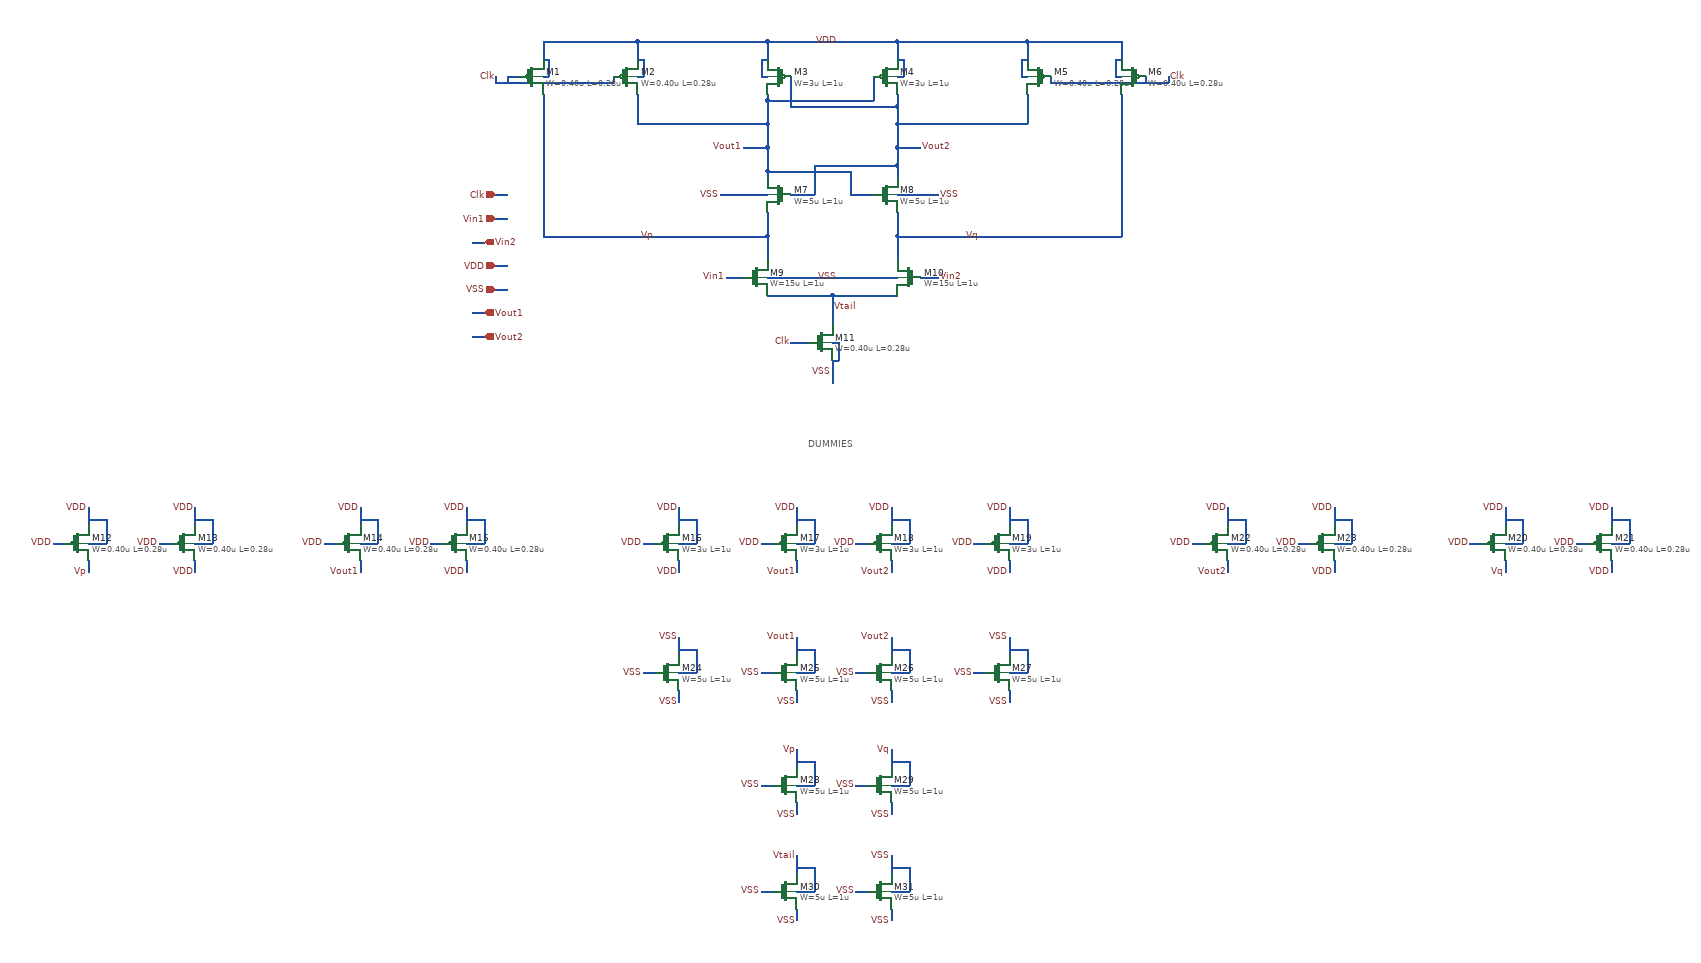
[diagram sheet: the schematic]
v {xschem version=3.4.8RC file_version=1.3}
G {}
K {}
V {}
S {}
F {}
E {}
P 4 1 2270 -1430 {}
T {DUMMIES} 2690 -860 0 0 0.4 0.4 {}
N 2730 -1100 2840 -1100 {lab=Vtail}
N 2730 -1100 2730 -1050 {lab=Vtail}
N 2840 -1200 2840 -1160 {lab=Vq}
N 2620 -1200 2620 -1160 {lab=Vp}
N 2730 -990 2730 -950 {lab=VSS}
N 2660 -1020 2690 -1020 {lab=Clk}
N 2550 -1130 2580 -1130 {lab=Vin1}
N 2880 -1130 2910 -1130 {lab=Vin2}
N 2240 -1440 2240 -1200 {lab=Vp}
N 2240 -1200 2620 -1200 {lab=Vp}
N 3220 -1440 3220 -1200 {lab=Vq}
N 2840 -1200 3220 -1200 {lab=Vq}
N 2620 -1310 2620 -1300 {lab=Vout1}
N 2840 -1320 2840 -1300 {lab=Vout2}
N 2660 -1270 2700 -1270 {lab=Vout2}
N 2700 -1320 2840 -1320 {lab=Vout2}
N 2760 -1270 2800 -1270 {lab=Vout1}
N 2760 -1310 2760 -1270 {lab=Vout1}
N 2620 -1310 2760 -1310 {lab=Vout1}
N 2700 -1320 2700 -1270 {lab=Vout2}
N 2400 -1440 2400 -1390 {lab=Vout1}
N 2400 -1390 2620 -1390 {lab=Vout1}
N 3060 -1440 3060 -1390 {lab=Vout2}
N 2840 -1390 3060 -1390 {lab=Vout2}
N 2800 -1470 2800 -1430 {lab=Vout1}
N 2620 -1430 2800 -1430 {lab=Vout1}
N 2660 -1470 2660 -1420 {lab=Vout2}
N 2660 -1420 2840 -1420 {lab=Vout2}
N 2580 -1350 2620 -1350 {lab=Vout1}
N 2840 -1350 2880 -1350 {lab=Vout2}
N 2160 -1460 2360 -1460 {lab=Clk}
N 3100 -1460 3300 -1460 {lab=Clk}
N 2240 -1530 2240 -1500 {lab=VDD}
N 3060 -1530 3220 -1530 {lab=VDD}
N 3220 -1530 3220 -1500 {lab=VDD}
N 3060 -1530 3060 -1500 {lab=VDD}
N 2840 -1530 2840 -1500 {lab=VDD}
N 2620 -1530 2620 -1500 {lab=VDD}
N 2400 -1530 2400 -1500 {lab=VDD}
N 2620 -1100 2730 -1100 {lab=Vtail}
N 2620 -1240 2620 -1200 {lab=Vp}
N 2840 -1240 2840 -1200 {lab=Vq}
N 2840 -1350 2840 -1320 {lab=Vout2}
N 2620 -1350 2620 -1310 {lab=Vout1}
N 2620 -1430 2620 -1390 {lab=Vout1}
N 2840 -1420 2840 -1390 {lab=Vout2}
N 2620 -1440 2620 -1430 {lab=Vout1}
N 2840 -1440 2840 -1420 {lab=Vout2}
N 2620 -1390 2620 -1350 {lab=Vout1}
N 2840 -1390 2840 -1350 {lab=Vout2}
N 2840 -1530 3060 -1530 {lab=VDD}
N 2620 -1530 2840 -1530 {lab=VDD}
N 2400 -1530 2620 -1530 {lab=VDD}
N 2240 -1530 2400 -1530 {lab=VDD}
N 2160 -1270 2180 -1270 {lab=Clk}
N 2160 -1230 2180 -1230 {lab=Vin1}
N 2120 -1190 2140 -1190 {lab=Vin2}
N 2160 -1150 2180 -1150 {lab=VDD}
N 2160 -1110 2180 -1110 {lab=VSS}
N 2120 -1070 2140 -1070 {lab=Vout1}
N 2120 -1030 2140 -1030 {lab=Vout2}
N 2360 -1470 2360 -1460 {lab=Clk}
N 2160 -1470 2160 -1460 {lab=Clk}
N 2240 -1470 2250 -1470 {lab=VDD}
N 2250 -1500 2250 -1470 {lab=VDD}
N 2240 -1500 2250 -1500 {lab=VDD}
N 2400 -1470 2410 -1470 {lab=VDD}
N 2410 -1500 2410 -1470 {lab=VDD}
N 2400 -1500 2410 -1500 {lab=VDD}
N 2610 -1470 2620 -1470 {lab=VDD}
N 2610 -1500 2610 -1470 {lab=VDD}
N 2610 -1500 2620 -1500 {lab=VDD}
N 2840 -1470 2850 -1470 {lab=VDD}
N 2850 -1500 2850 -1470 {lab=VDD}
N 2840 -1500 2850 -1500 {lab=VDD}
N 3050 -1470 3060 -1470 {lab=VDD}
N 3050 -1500 3050 -1470 {lab=VDD}
N 3050 -1500 3060 -1500 {lab=VDD}
N 3100 -1470 3100 -1460 {lab=Clk}
N 3260 -1470 3260 -1460 {lab=Clk}
N 3300 -1470 3300 -1460 {lab=Clk}
N 3210 -1470 3220 -1470 {lab=VDD}
N 3210 -1500 3210 -1470 {lab=VDD}
N 3210 -1500 3220 -1500 {lab=VDD}
N 2610 -1270 2620 -1270 {lab=VSS}
N 2840 -1270 2850 -1270 {lab=VSS}
N 2620 -1130 2630 -1130 {lab=VSS}
N 2830 -1130 2840 -1130 {lab=VSS}
N 2730 -1020 2740 -1020 {lab=VSS}
N 2740 -1020 2740 -990 {lab=VSS}
N 2730 -990 2740 -990 {lab=VSS}
N 2190 -1470 2200 -1470 {lab=Clk}
N 2180 -1470 2190 -1470 {lab=Clk}
N 2180 -1470 2180 -1460 {lab=Clk}
N 2740 -1130 2830 -1130 {lab=VSS}
N 2630 -1130 2740 -1130 {lab=VSS}
N 2850 -1270 2910 -1270 {lab=VSS}
N 2540 -1270 2610 -1270 {lab=VSS}
N 1410 -680 1430 -680 {lab=VDD}
N 1470 -740 1470 -710 {lab=VDD}
N 1470 -680 1500 -680 {lab=VDD}
N 1500 -720 1500 -680 {lab=VDD}
N 1470 -720 1500 -720 {lab=VDD}
N 1470 -650 1470 -630 {lab=Vp}
N 1590 -680 1610 -680 {lab=VDD}
N 1650 -740 1650 -710 {lab=VDD}
N 1650 -680 1680 -680 {lab=VDD}
N 1680 -720 1680 -680 {lab=VDD}
N 1650 -720 1680 -720 {lab=VDD}
N 1650 -650 1650 -630 {lab=VDD}
N 1870 -680 1890 -680 {lab=VDD}
N 1930 -740 1930 -710 {lab=VDD}
N 1930 -680 1960 -680 {lab=VDD}
N 1960 -720 1960 -680 {lab=VDD}
N 1930 -720 1960 -720 {lab=VDD}
N 1930 -650 1930 -630 {lab=Vout1}
N 2050 -680 2070 -680 {lab=VDD}
N 2110 -740 2110 -710 {lab=VDD}
N 2110 -680 2140 -680 {lab=VDD}
N 2140 -720 2140 -680 {lab=VDD}
N 2110 -720 2140 -720 {lab=VDD}
N 2110 -650 2110 -630 {lab=VDD}
N 2410 -680 2430 -680 {lab=VDD}
N 2470 -740 2470 -710 {lab=VDD}
N 2470 -680 2500 -680 {lab=VDD}
N 2500 -720 2500 -680 {lab=VDD}
N 2470 -720 2500 -720 {lab=VDD}
N 2470 -650 2470 -630 {lab=VDD}
N 2610 -680 2630 -680 {lab=VDD}
N 2670 -740 2670 -710 {lab=VDD}
N 2670 -680 2700 -680 {lab=VDD}
N 2700 -720 2700 -680 {lab=VDD}
N 2670 -720 2700 -720 {lab=VDD}
N 2670 -650 2670 -630 {lab=Vout1}
N 2770 -680 2790 -680 {lab=VDD}
N 2830 -740 2830 -710 {lab=VDD}
N 2830 -680 2860 -680 {lab=VDD}
N 2860 -720 2860 -680 {lab=VDD}
N 2830 -720 2860 -720 {lab=VDD}
N 2830 -650 2830 -630 {lab=Vout2}
N 2970 -680 2990 -680 {lab=VDD}
N 3030 -740 3030 -710 {lab=VDD}
N 3030 -680 3060 -680 {lab=VDD}
N 3060 -720 3060 -680 {lab=VDD}
N 3030 -720 3060 -720 {lab=VDD}
N 3030 -650 3030 -630 {lab=VDD}
N 3810 -680 3830 -680 {lab=VDD}
N 3870 -740 3870 -710 {lab=VDD}
N 3870 -680 3900 -680 {lab=VDD}
N 3900 -720 3900 -680 {lab=VDD}
N 3870 -720 3900 -720 {lab=VDD}
N 3870 -650 3870 -630 {lab=Vq}
N 3990 -680 4010 -680 {lab=VDD}
N 4050 -740 4050 -710 {lab=VDD}
N 4050 -680 4080 -680 {lab=VDD}
N 4080 -720 4080 -680 {lab=VDD}
N 4050 -720 4080 -720 {lab=VDD}
N 4050 -650 4050 -630 {lab=VDD}
N 3340 -680 3360 -680 {lab=VDD}
N 3400 -740 3400 -710 {lab=VDD}
N 3400 -680 3430 -680 {lab=VDD}
N 3430 -720 3430 -680 {lab=VDD}
N 3400 -720 3430 -720 {lab=VDD}
N 3400 -650 3400 -630 {lab=Vout2}
N 3520 -680 3540 -680 {lab=VDD}
N 3580 -740 3580 -710 {lab=VDD}
N 3580 -680 3610 -680 {lab=VDD}
N 3610 -720 3610 -680 {lab=VDD}
N 3580 -720 3610 -720 {lab=VDD}
N 3580 -650 3580 -630 {lab=VDD}
N 2410 -460 2430 -460 {lab=VSS}
N 2470 -520 2470 -490 {lab=VSS}
N 2470 -460 2500 -460 {lab=VSS}
N 2500 -500 2500 -460 {lab=VSS}
N 2470 -500 2500 -500 {lab=VSS}
N 2470 -430 2470 -410 {lab=VSS}
N 2610 -460 2630 -460 {lab=VSS}
N 2670 -520 2670 -490 {lab=Vout1}
N 2670 -460 2700 -460 {lab=Vout1}
N 2700 -500 2700 -460 {lab=Vout1}
N 2670 -500 2700 -500 {lab=Vout1}
N 2670 -430 2670 -410 {lab=VSS}
N 2770 -460 2790 -460 {lab=VSS}
N 2830 -520 2830 -490 {lab=Vout2}
N 2830 -460 2860 -460 {lab=Vout2}
N 2860 -500 2860 -460 {lab=Vout2}
N 2830 -500 2860 -500 {lab=Vout2}
N 2830 -430 2830 -410 {lab=VSS}
N 2970 -460 2990 -460 {lab=VSS}
N 3030 -520 3030 -490 {lab=VSS}
N 3030 -460 3060 -460 {lab=VSS}
N 3060 -500 3060 -460 {lab=VSS}
N 3030 -500 3060 -500 {lab=VSS}
N 3030 -430 3030 -410 {lab=VSS}
N 2610 -270 2630 -270 {lab=VSS}
N 2670 -330 2670 -300 {lab=Vp}
N 2670 -270 2700 -270 {lab=Vp}
N 2700 -310 2700 -270 {lab=Vp}
N 2670 -310 2700 -310 {lab=Vp}
N 2670 -240 2670 -220 {lab=VSS}
N 2770 -270 2790 -270 {lab=VSS}
N 2830 -330 2830 -300 {lab=Vq}
N 2830 -270 2860 -270 {lab=Vq}
N 2860 -310 2860 -270 {lab=Vq}
N 2830 -310 2860 -310 {lab=Vq}
N 2830 -240 2830 -220 {lab=VSS}
N 2610 -90 2630 -90 {lab=VSS}
N 2670 -150 2670 -120 {lab=Vtail}
N 2670 -90 2700 -90 {lab=Vtail}
N 2700 -130 2700 -90 {lab=Vtail}
N 2670 -130 2700 -130 {lab=Vtail}
N 2670 -60 2670 -40 {lab=VSS}
N 2770 -90 2790 -90 {lab=VSS}
N 2830 -150 2830 -120 {lab=#net1}
N 2830 -90 2860 -90 {lab=#net1}
N 2860 -130 2860 -90 {lab=#net1}
N 2830 -130 2860 -130 {lab=#net1}
N 2830 -60 2830 -40 {lab=VSS}
C {symbols/pfet_03v3.sym} 2220 -1470 0 0 {name=M1
L=0.28u
W=0.40u
nf=1
m=1
ad="'int((nf+1)/2) * W/nf * 0.18u'"
pd="'2*int((nf+1)/2) * (W/nf + 0.18u)'"
as="'int((nf+2)/2) * W/nf * 0.18u'"
ps="'2*int((nf+2)/2) * (W/nf + 0.18u)'"
nrd="'0.18u / W'" nrs="'0.18u / W'"
sa=0 sb=0 sd=0
model=pfet_03v3
spiceprefix=X
}
C {symbols/pfet_03v3.sym} 2380 -1470 0 0 {name=M2
L=0.28u
W=0.40u
nf=1
m=1
ad="'int((nf+1)/2) * W/nf * 0.18u'"
pd="'2*int((nf+1)/2) * (W/nf + 0.18u)'"
as="'int((nf+2)/2) * W/nf * 0.18u'"
ps="'2*int((nf+2)/2) * (W/nf + 0.18u)'"
nrd="'0.18u / W'" nrs="'0.18u / W'"
sa=0 sb=0 sd=0
model=pfet_03v3
spiceprefix=X
}
C {symbols/pfet_03v3.sym} 2640 -1470 0 1 {name=M3
L=1u
W=3u
nf=1
m=1
ad="'int((nf+1)/2) * W/nf * 0.18u'"
pd="'2*int((nf+1)/2) * (W/nf + 0.18u)'"
as="'int((nf+2)/2) * W/nf * 0.18u'"
ps="'2*int((nf+2)/2) * (W/nf + 0.18u)'"
nrd="'0.18u / W'" nrs="'0.18u / W'"
sa=0 sb=0 sd=0
model=pfet_03v3
spiceprefix=X
}
C {symbols/pfet_03v3.sym} 2820 -1470 0 0 {name=M4
L=1u
W=3u
nf=1
m=1
ad="'int((nf+1)/2) * W/nf * 0.18u'"
pd="'2*int((nf+1)/2) * (W/nf + 0.18u)'"
as="'int((nf+2)/2) * W/nf * 0.18u'"
ps="'2*int((nf+2)/2) * (W/nf + 0.18u)'"
nrd="'0.18u / W'" nrs="'0.18u / W'"
sa=0 sb=0 sd=0
model=pfet_03v3
spiceprefix=X
}
C {symbols/pfet_03v3.sym} 3080 -1470 0 1 {name=M5
L=0.28u
W=0.40u
nf=1
m=1
ad="'int((nf+1)/2) * W/nf * 0.18u'"
pd="'2*int((nf+1)/2) * (W/nf + 0.18u)'"
as="'int((nf+2)/2) * W/nf * 0.18u'"
ps="'2*int((nf+2)/2) * (W/nf + 0.18u)'"
nrd="'0.18u / W'" nrs="'0.18u / W'"
sa=0 sb=0 sd=0
model=pfet_03v3
spiceprefix=X
}
C {symbols/pfet_03v3.sym} 3240 -1470 0 1 {name=M6
L=0.28u
W=0.40u
nf=1
m=1
ad="'int((nf+1)/2) * W/nf * 0.18u'"
pd="'2*int((nf+1)/2) * (W/nf + 0.18u)'"
as="'int((nf+2)/2) * W/nf * 0.18u'"
ps="'2*int((nf+2)/2) * (W/nf + 0.18u)'"
nrd="'0.18u / W'" nrs="'0.18u / W'"
sa=0 sb=0 sd=0
model=pfet_03v3
spiceprefix=X
}
C {symbols/nfet_03v3.sym} 2640 -1270 0 1 {name=M7
L=1u
W=5u
nf=1
m=1
ad="'int((nf+1)/2) * W/nf * 0.18u'"
pd="'2*int((nf+1)/2) * (W/nf + 0.18u)'"
as="'int((nf+2)/2) * W/nf * 0.18u'"
ps="'2*int((nf+2)/2) * (W/nf + 0.18u)'"
nrd="'0.18u / W'" nrs="'0.18u / W'"
sa=0 sb=0 sd=0
model=nfet_03v3
spiceprefix=X
}
C {symbols/nfet_03v3.sym} 2820 -1270 0 0 {name=M8
L=1u
W=5u
nf=1
m=1
ad="'int((nf+1)/2) * W/nf * 0.18u'"
pd="'2*int((nf+1)/2) * (W/nf + 0.18u)'"
as="'int((nf+2)/2) * W/nf * 0.18u'"
ps="'2*int((nf+2)/2) * (W/nf + 0.18u)'"
nrd="'0.18u / W'" nrs="'0.18u / W'"
sa=0 sb=0 sd=0
model=nfet_03v3
spiceprefix=X
}
C {symbols/nfet_03v3.sym} 2600 -1130 0 0 {name=M9
L=1u
W=15u
nf=1
m=1
ad="'int((nf+1)/2) * W/nf * 0.18u'"
pd="'2*int((nf+1)/2) * (W/nf + 0.18u)'"
as="'int((nf+2)/2) * W/nf * 0.18u'"
ps="'2*int((nf+2)/2) * (W/nf + 0.18u)'"
nrd="'0.18u / W'" nrs="'0.18u / W'"
sa=0 sb=0 sd=0
model=nfet_03v3
spiceprefix=X
}
C {symbols/nfet_03v3.sym} 2860 -1130 0 1 {name=M10
L=1u
W=15u
nf=1
m=1
ad="'int((nf+1)/2) * W/nf * 0.18u'"
pd="'2*int((nf+1)/2) * (W/nf + 0.18u)'"
as="'int((nf+2)/2) * W/nf * 0.18u'"
ps="'2*int((nf+2)/2) * (W/nf + 0.18u)'"
nrd="'0.18u / W'" nrs="'0.18u / W'"
sa=0 sb=0 sd=0
model=nfet_03v3
spiceprefix=X
}
C {symbols/nfet_03v3.sym} 2710 -1020 0 0 {name=M11
L=0.28u
W=0.40u
nf=1
m=1
ad="'int((nf+1)/2) * W/nf * 0.18u'"
pd="'2*int((nf+1)/2) * (W/nf + 0.18u)'"
as="'int((nf+2)/2) * W/nf * 0.18u'"
ps="'2*int((nf+2)/2) * (W/nf + 0.18u)'"
nrd="'0.18u / W'" nrs="'0.18u / W'"
sa=0 sb=0 sd=0
model=nfet_03v3
spiceprefix=X
}
C {ipin.sym} 2160 -1270 0 0 {name=p1 lab=Clk}
C {ipin.sym} 2160 -1230 0 0 {name=p2 lab=Vin1}
C {ipin.sym} 2140 -1190 0 1 {name=p3 lab=Vin2}
C {iopin.sym} 2160 -1150 2 0 {name=p4 lab=VDD}
C {iopin.sym} 2160 -1110 2 0 {name=p5 lab=VSS}
C {opin.sym} 2140 -1070 0 0 {name=p6 lab=Vout1}
C {opin.sym} 2140 -1030 0 0 {name=p7 lab=Vout2}
C {lab_pin.sym} 2730 -970 0 0 {name=p8 sig_type=std_logic lab=VSS}
C {lab_pin.sym} 2660 -1020 0 0 {name=p9 sig_type=std_logic lab=Clk}
C {lab_pin.sym} 2550 -1130 0 0 {name=p10 sig_type=std_logic lab=Vin1}
C {lab_pin.sym} 2910 -1130 0 1 {name=p11 sig_type=std_logic lab=Vin2}
C {lab_pin.sym} 2580 -1350 0 0 {name=p12 sig_type=std_logic lab=Vout1}
C {lab_pin.sym} 2880 -1350 0 1 {name=p13 sig_type=std_logic lab=Vout2}
C {lab_pin.sym} 2160 -1470 0 0 {name=p14 sig_type=std_logic lab=Clk}
C {lab_pin.sym} 3300 -1470 0 1 {name=p15 sig_type=std_logic lab=Clk}
C {lab_pin.sym} 2740 -1530 1 0 {name=p16 sig_type=std_logic lab=VDD}
C {lab_pin.sym} 2430 -1200 1 0 {name=p17 sig_type=std_logic lab=Vp}
C {lab_pin.sym} 2980 -1200 1 0 {name=p18 sig_type=std_logic lab=Vq}
C {lab_pin.sym} 2540 -1270 0 0 {name=p19 sig_type=std_logic lab=VSS}
C {lab_pin.sym} 2910 -1270 0 1 {name=p20 sig_type=std_logic lab=VSS}
C {lab_pin.sym} 2740 -1130 3 1 {name=p22 sig_type=std_logic lab=VSS}
C {symbols/pfet_03v3.sym} 1450 -680 0 0 {name=M12
L=0.28u
W=0.40u
nf=1
m=1
ad="'int((nf+1)/2) * W/nf * 0.18u'"
pd="'2*int((nf+1)/2) * (W/nf + 0.18u)'"
as="'int((nf+2)/2) * W/nf * 0.18u'"
ps="'2*int((nf+2)/2) * (W/nf + 0.18u)'"
nrd="'0.18u / W'" nrs="'0.18u / W'"
sa=0 sb=0 sd=0
model=pfet_03v3
spiceprefix=X
}
C {lab_pin.sym} 1410 -680 0 0 {name=p21 sig_type=std_logic lab=VDD}
C {lab_pin.sym} 1470 -740 0 0 {name=p23 sig_type=std_logic lab=VDD}
C {lab_pin.sym} 1470 -630 0 0 {name=p24 sig_type=std_logic lab=Vp}
C {symbols/pfet_03v3.sym} 1630 -680 0 0 {name=M13
L=0.28u
W=0.40u
nf=1
m=1
ad="'int((nf+1)/2) * W/nf * 0.18u'"
pd="'2*int((nf+1)/2) * (W/nf + 0.18u)'"
as="'int((nf+2)/2) * W/nf * 0.18u'"
ps="'2*int((nf+2)/2) * (W/nf + 0.18u)'"
nrd="'0.18u / W'" nrs="'0.18u / W'"
sa=0 sb=0 sd=0
model=pfet_03v3
spiceprefix=X
}
C {lab_pin.sym} 1590 -680 0 0 {name=p25 sig_type=std_logic lab=VDD}
C {lab_pin.sym} 1650 -740 0 0 {name=p26 sig_type=std_logic lab=VDD}
C {lab_pin.sym} 1650 -630 0 0 {name=p27 sig_type=std_logic lab=VDD}
C {symbols/pfet_03v3.sym} 1910 -680 0 0 {name=M14
L=0.28u
W=0.40u
nf=1
m=1
ad="'int((nf+1)/2) * W/nf * 0.18u'"
pd="'2*int((nf+1)/2) * (W/nf + 0.18u)'"
as="'int((nf+2)/2) * W/nf * 0.18u'"
ps="'2*int((nf+2)/2) * (W/nf + 0.18u)'"
nrd="'0.18u / W'" nrs="'0.18u / W'"
sa=0 sb=0 sd=0
model=pfet_03v3
spiceprefix=X
}
C {lab_pin.sym} 1870 -680 0 0 {name=p28 sig_type=std_logic lab=VDD}
C {lab_pin.sym} 1930 -740 0 0 {name=p29 sig_type=std_logic lab=VDD}
C {lab_pin.sym} 1930 -630 0 0 {name=p30 sig_type=std_logic lab=Vout1}
C {symbols/pfet_03v3.sym} 2090 -680 0 0 {name=M15
L=0.28u
W=0.40u
nf=1
m=1
ad="'int((nf+1)/2) * W/nf * 0.18u'"
pd="'2*int((nf+1)/2) * (W/nf + 0.18u)'"
as="'int((nf+2)/2) * W/nf * 0.18u'"
ps="'2*int((nf+2)/2) * (W/nf + 0.18u)'"
nrd="'0.18u / W'" nrs="'0.18u / W'"
sa=0 sb=0 sd=0
model=pfet_03v3
spiceprefix=X
}
C {lab_pin.sym} 2050 -680 0 0 {name=p31 sig_type=std_logic lab=VDD}
C {lab_pin.sym} 2110 -740 0 0 {name=p32 sig_type=std_logic lab=VDD}
C {lab_pin.sym} 2110 -630 0 0 {name=p33 sig_type=std_logic lab=VDD}
C {symbols/pfet_03v3.sym} 2450 -680 0 0 {name=M16
L=1u
W=3u
nf=1
m=1
ad="'int((nf+1)/2) * W/nf * 0.18u'"
pd="'2*int((nf+1)/2) * (W/nf + 0.18u)'"
as="'int((nf+2)/2) * W/nf * 0.18u'"
ps="'2*int((nf+2)/2) * (W/nf + 0.18u)'"
nrd="'0.18u / W'" nrs="'0.18u / W'"
sa=0 sb=0 sd=0
model=pfet_03v3
spiceprefix=X
}
C {lab_pin.sym} 2410 -680 0 0 {name=p34 sig_type=std_logic lab=VDD}
C {lab_pin.sym} 2470 -740 0 0 {name=p35 sig_type=std_logic lab=VDD}
C {lab_pin.sym} 2470 -630 0 0 {name=p36 sig_type=std_logic lab=VDD}
C {symbols/pfet_03v3.sym} 2650 -680 0 0 {name=M17
L=1u
W=3u
nf=1
m=1
ad="'int((nf+1)/2) * W/nf * 0.18u'"
pd="'2*int((nf+1)/2) * (W/nf + 0.18u)'"
as="'int((nf+2)/2) * W/nf * 0.18u'"
ps="'2*int((nf+2)/2) * (W/nf + 0.18u)'"
nrd="'0.18u / W'" nrs="'0.18u / W'"
sa=0 sb=0 sd=0
model=pfet_03v3
spiceprefix=X
}
C {lab_pin.sym} 2610 -680 0 0 {name=p37 sig_type=std_logic lab=VDD}
C {lab_pin.sym} 2670 -740 0 0 {name=p38 sig_type=std_logic lab=VDD}
C {symbols/pfet_03v3.sym} 2810 -680 0 0 {name=M18
L=1u
W=3u
nf=1
m=1
ad="'int((nf+1)/2) * W/nf * 0.18u'"
pd="'2*int((nf+1)/2) * (W/nf + 0.18u)'"
as="'int((nf+2)/2) * W/nf * 0.18u'"
ps="'2*int((nf+2)/2) * (W/nf + 0.18u)'"
nrd="'0.18u / W'" nrs="'0.18u / W'"
sa=0 sb=0 sd=0
model=pfet_03v3
spiceprefix=X
}
C {lab_pin.sym} 2770 -680 0 0 {name=p40 sig_type=std_logic lab=VDD}
C {lab_pin.sym} 2830 -740 0 0 {name=p41 sig_type=std_logic lab=VDD}
C {lab_pin.sym} 2670 -630 0 0 {name=p39 sig_type=std_logic lab=Vout1}
C {lab_pin.sym} 2830 -630 0 0 {name=p42 sig_type=std_logic lab=Vout2}
C {symbols/pfet_03v3.sym} 3010 -680 0 0 {name=M19
L=1u
W=3u
nf=1
m=1
ad="'int((nf+1)/2) * W/nf * 0.18u'"
pd="'2*int((nf+1)/2) * (W/nf + 0.18u)'"
as="'int((nf+2)/2) * W/nf * 0.18u'"
ps="'2*int((nf+2)/2) * (W/nf + 0.18u)'"
nrd="'0.18u / W'" nrs="'0.18u / W'"
sa=0 sb=0 sd=0
model=pfet_03v3
spiceprefix=X
}
C {lab_pin.sym} 2970 -680 0 0 {name=p43 sig_type=std_logic lab=VDD}
C {lab_pin.sym} 3030 -740 0 0 {name=p44 sig_type=std_logic lab=VDD}
C {lab_pin.sym} 3030 -630 0 0 {name=p45 sig_type=std_logic lab=VDD}
C {symbols/pfet_03v3.sym} 3850 -680 0 0 {name=M20
L=0.28u
W=0.40u
nf=1
m=1
ad="'int((nf+1)/2) * W/nf * 0.18u'"
pd="'2*int((nf+1)/2) * (W/nf + 0.18u)'"
as="'int((nf+2)/2) * W/nf * 0.18u'"
ps="'2*int((nf+2)/2) * (W/nf + 0.18u)'"
nrd="'0.18u / W'" nrs="'0.18u / W'"
sa=0 sb=0 sd=0
model=pfet_03v3
spiceprefix=X
}
C {lab_pin.sym} 3810 -680 0 0 {name=p46 sig_type=std_logic lab=VDD}
C {lab_pin.sym} 3870 -740 0 0 {name=p47 sig_type=std_logic lab=VDD}
C {lab_pin.sym} 3870 -630 0 0 {name=p48 sig_type=std_logic lab=Vq}
C {symbols/pfet_03v3.sym} 4030 -680 0 0 {name=M21
L=0.28u
W=0.40u
nf=1
m=1
ad="'int((nf+1)/2) * W/nf * 0.18u'"
pd="'2*int((nf+1)/2) * (W/nf + 0.18u)'"
as="'int((nf+2)/2) * W/nf * 0.18u'"
ps="'2*int((nf+2)/2) * (W/nf + 0.18u)'"
nrd="'0.18u / W'" nrs="'0.18u / W'"
sa=0 sb=0 sd=0
model=pfet_03v3
spiceprefix=X
}
C {lab_pin.sym} 3990 -680 0 0 {name=p49 sig_type=std_logic lab=VDD}
C {lab_pin.sym} 4050 -740 0 0 {name=p50 sig_type=std_logic lab=VDD}
C {lab_pin.sym} 4050 -630 0 0 {name=p51 sig_type=std_logic lab=VDD}
C {symbols/pfet_03v3.sym} 3380 -680 0 0 {name=M22
L=0.28u
W=0.40u
nf=1
m=1
ad="'int((nf+1)/2) * W/nf * 0.18u'"
pd="'2*int((nf+1)/2) * (W/nf + 0.18u)'"
as="'int((nf+2)/2) * W/nf * 0.18u'"
ps="'2*int((nf+2)/2) * (W/nf + 0.18u)'"
nrd="'0.18u / W'" nrs="'0.18u / W'"
sa=0 sb=0 sd=0
model=pfet_03v3
spiceprefix=X
}
C {lab_pin.sym} 3340 -680 0 0 {name=p52 sig_type=std_logic lab=VDD}
C {lab_pin.sym} 3400 -740 0 0 {name=p53 sig_type=std_logic lab=VDD}
C {lab_pin.sym} 3400 -630 0 0 {name=p54 sig_type=std_logic lab=Vout2}
C {symbols/pfet_03v3.sym} 3560 -680 0 0 {name=M23
L=0.28u
W=0.40u
nf=1
m=1
ad="'int((nf+1)/2) * W/nf * 0.18u'"
pd="'2*int((nf+1)/2) * (W/nf + 0.18u)'"
as="'int((nf+2)/2) * W/nf * 0.18u'"
ps="'2*int((nf+2)/2) * (W/nf + 0.18u)'"
nrd="'0.18u / W'" nrs="'0.18u / W'"
sa=0 sb=0 sd=0
model=pfet_03v3
spiceprefix=X
}
C {lab_pin.sym} 3520 -680 0 0 {name=p55 sig_type=std_logic lab=VDD}
C {lab_pin.sym} 3580 -740 0 0 {name=p56 sig_type=std_logic lab=VDD}
C {lab_pin.sym} 3580 -630 0 0 {name=p57 sig_type=std_logic lab=VDD}
C {symbols/nfet_03v3.sym} 2450 -460 0 0 {name=M24
L=1u
W=5u
nf=1
m=1
ad="'int((nf+1)/2) * W/nf * 0.18u'"
pd="'2*int((nf+1)/2) * (W/nf + 0.18u)'"
as="'int((nf+2)/2) * W/nf * 0.18u'"
ps="'2*int((nf+2)/2) * (W/nf + 0.18u)'"
nrd="'0.18u / W'" nrs="'0.18u / W'"
sa=0 sb=0 sd=0
model=nfet_03v3
spiceprefix=X
}
C {lab_pin.sym} 2610 -460 0 0 {name=p61 sig_type=std_logic lab=VSS}
C {lab_pin.sym} 2670 -520 0 0 {name=p62 sig_type=std_logic lab=Vout1}
C {lab_pin.sym} 2670 -410 0 0 {name=p65 sig_type=std_logic lab=VSS}
C {lab_pin.sym} 2830 -520 0 0 {name=p66 sig_type=std_logic lab=Vout2}
C {symbols/nfet_03v3.sym} 2650 -460 0 0 {name=M25
L=1u
W=5u
nf=1
m=1
ad="'int((nf+1)/2) * W/nf * 0.18u'"
pd="'2*int((nf+1)/2) * (W/nf + 0.18u)'"
as="'int((nf+2)/2) * W/nf * 0.18u'"
ps="'2*int((nf+2)/2) * (W/nf + 0.18u)'"
nrd="'0.18u / W'" nrs="'0.18u / W'"
sa=0 sb=0 sd=0
model=nfet_03v3
spiceprefix=X
}
C {symbols/nfet_03v3.sym} 2810 -460 0 0 {name=M26
L=1u
W=5u
nf=1
m=1
ad="'int((nf+1)/2) * W/nf * 0.18u'"
pd="'2*int((nf+1)/2) * (W/nf + 0.18u)'"
as="'int((nf+2)/2) * W/nf * 0.18u'"
ps="'2*int((nf+2)/2) * (W/nf + 0.18u)'"
nrd="'0.18u / W'" nrs="'0.18u / W'"
sa=0 sb=0 sd=0
model=nfet_03v3
spiceprefix=X
}
C {symbols/nfet_03v3.sym} 3010 -460 0 0 {name=M27
L=1u
W=5u
nf=1
m=1
ad="'int((nf+1)/2) * W/nf * 0.18u'"
pd="'2*int((nf+1)/2) * (W/nf + 0.18u)'"
as="'int((nf+2)/2) * W/nf * 0.18u'"
ps="'2*int((nf+2)/2) * (W/nf + 0.18u)'"
nrd="'0.18u / W'" nrs="'0.18u / W'"
sa=0 sb=0 sd=0
model=nfet_03v3
spiceprefix=X
}
C {lab_pin.sym} 2470 -520 0 0 {name=p58 sig_type=std_logic lab=VSS}
C {lab_pin.sym} 2410 -460 0 0 {name=p59 sig_type=std_logic lab=VSS}
C {lab_pin.sym} 2470 -410 0 0 {name=p60 sig_type=std_logic lab=VSS}
C {lab_pin.sym} 2770 -460 0 0 {name=p63 sig_type=std_logic lab=VSS}
C {lab_pin.sym} 2830 -410 0 0 {name=p64 sig_type=std_logic lab=VSS}
C {lab_pin.sym} 3030 -410 0 0 {name=p67 sig_type=std_logic lab=VSS}
C {lab_pin.sym} 2970 -460 0 0 {name=p68 sig_type=std_logic lab=VSS}
C {lab_pin.sym} 3030 -520 0 0 {name=p69 sig_type=std_logic lab=VSS}
C {lab_pin.sym} 2610 -270 0 0 {name=p70 sig_type=std_logic lab=VSS}
C {lab_pin.sym} 2670 -330 0 0 {name=p71 sig_type=std_logic lab=Vp}
C {lab_pin.sym} 2670 -220 0 0 {name=p72 sig_type=std_logic lab=VSS}
C {lab_pin.sym} 2830 -330 0 0 {name=p73 sig_type=std_logic lab=Vq}
C {symbols/nfet_03v3.sym} 2650 -270 0 0 {name=M28
L=1u
W=5u
nf=1
m=1
ad="'int((nf+1)/2) * W/nf * 0.18u'"
pd="'2*int((nf+1)/2) * (W/nf + 0.18u)'"
as="'int((nf+2)/2) * W/nf * 0.18u'"
ps="'2*int((nf+2)/2) * (W/nf + 0.18u)'"
nrd="'0.18u / W'" nrs="'0.18u / W'"
sa=0 sb=0 sd=0
model=nfet_03v3
spiceprefix=X
}
C {symbols/nfet_03v3.sym} 2810 -270 0 0 {name=M29
L=1u
W=5u
nf=1
m=1
ad="'int((nf+1)/2) * W/nf * 0.18u'"
pd="'2*int((nf+1)/2) * (W/nf + 0.18u)'"
as="'int((nf+2)/2) * W/nf * 0.18u'"
ps="'2*int((nf+2)/2) * (W/nf + 0.18u)'"
nrd="'0.18u / W'" nrs="'0.18u / W'"
sa=0 sb=0 sd=0
model=nfet_03v3
spiceprefix=X
}
C {lab_pin.sym} 2770 -270 0 0 {name=p74 sig_type=std_logic lab=VSS}
C {lab_pin.sym} 2830 -220 0 0 {name=p75 sig_type=std_logic lab=VSS}
C {lab_pin.sym} 2610 -90 0 0 {name=p76 sig_type=std_logic lab=VSS}
C {lab_pin.sym} 2670 -40 0 0 {name=p78 sig_type=std_logic lab=VSS}
C {symbols/nfet_03v3.sym} 2650 -90 0 0 {name=M30
L=1u
W=5u
nf=1
m=1
ad="'int((nf+1)/2) * W/nf * 0.18u'"
pd="'2*int((nf+1)/2) * (W/nf + 0.18u)'"
as="'int((nf+2)/2) * W/nf * 0.18u'"
ps="'2*int((nf+2)/2) * (W/nf + 0.18u)'"
nrd="'0.18u / W'" nrs="'0.18u / W'"
sa=0 sb=0 sd=0
model=nfet_03v3
spiceprefix=X
}
C {symbols/nfet_03v3.sym} 2810 -90 0 0 {name=M31
L=1u
W=5u
nf=1
m=1
ad="'int((nf+1)/2) * W/nf * 0.18u'"
pd="'2*int((nf+1)/2) * (W/nf + 0.18u)'"
as="'int((nf+2)/2) * W/nf * 0.18u'"
ps="'2*int((nf+2)/2) * (W/nf + 0.18u)'"
nrd="'0.18u / W'" nrs="'0.18u / W'"
sa=0 sb=0 sd=0
model=nfet_03v3
spiceprefix=X
}
C {lab_pin.sym} 2770 -90 0 0 {name=p80 sig_type=std_logic lab=VSS}
C {lab_pin.sym} 2830 -40 0 0 {name=p81 sig_type=std_logic lab=VSS}
C {lab_pin.sym} 2730 -1080 0 1 {name=p82 sig_type=std_logic lab=Vtail}
C {lab_pin.sym} 2670 -150 0 0 {name=p83 sig_type=std_logic lab=Vtail}
C {lab_pin.sym} 2830 -150 0 0 {name=p77 sig_type=std_logic lab=VSS}
